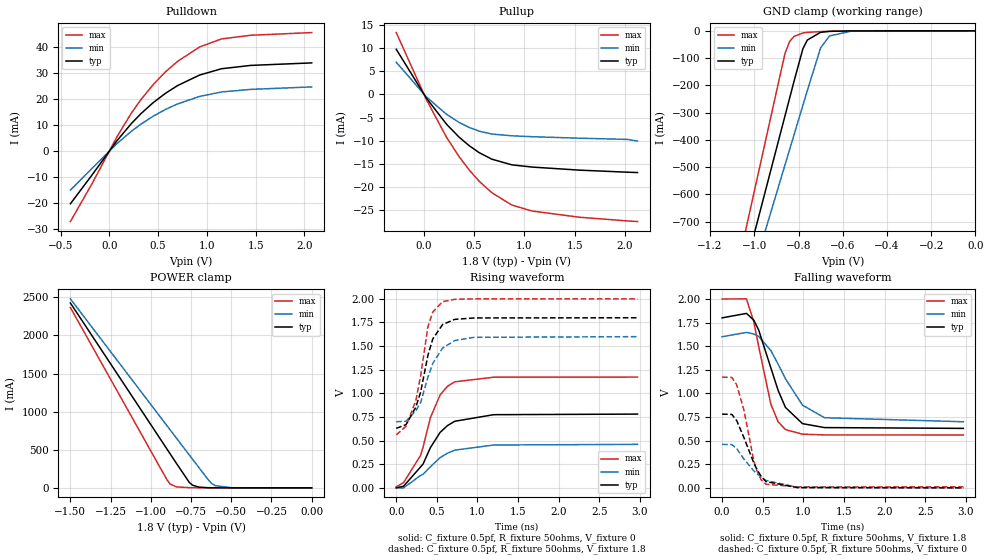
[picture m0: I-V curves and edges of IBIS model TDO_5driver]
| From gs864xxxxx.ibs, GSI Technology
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|  signals   TDO
[Model]   TDO_5driver
Model_type   3-state
Polarity   Non-Inverting
Vmeas =   0.9v
Cref  =   0pF
Rref  =   50
Vref  =   0.9v
|  variable   typ   min   max
C_comp   3.0pF   2.5pF   3.5pF
|  variable   typ   min   max
[Temperature Range]   50   0   100
|  variable   typ   min   max
[Voltage Range]   1.8   1.6   2.0
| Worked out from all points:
|   slope of the pulldown table from 0 to 0.27 V, typ, clamps not added: 22 ohm
|   slope of the pullup table from 0 to 0.27 V, typ, clamps not added: 35.9 ohm
|   GND clamp passes 1 mA (typ) near -0.63 V on its own axis
|   POWER clamp passes 1 mA (typ) near -0.62 V on its own axis
|   rising waveform, C_fixture 0.5pf, R_fixture 50ohms, V_fixture 0: 20-80 % time 364ps typ, 408ps min, 296ps max; typ from 0 V to 0.78 V
|   rising waveform, C_fixture 0.5pf, R_fixture 50ohms, V_fixture 1.8: 20-80 % time 201ps typ, 228ps min, 181ps max; typ from 0.63 V to 1.8 V
|   falling waveform, C_fixture 0.5pf, R_fixture 50ohms, V_fixture 1.8: 20-80 % time 278ps typ, 363ps min, 213ps max; typ from 1.8 V to 0.63 V
|   falling waveform, C_fixture 0.5pf, R_fixture 50ohms, V_fixture 0: 20-80 % time 227ps typ, 293ps min, 168ps max; typ from 0.78 V to 0 V
[Pulldown]
| voltage   I(typ)   I(min)   I(max)
-400mV    -20.27mA   -15.02mA   -27.07mA
-175mV    -9.067mA   -6.592mA   -12.36mA
75mV      3.788mA    2.71mA     5.252mA
225mV     10.47mA    7.513mA    14.46mA
325mV     14.33mA    10.29mA    19.74mA
450mV     18.52mA    13.32mA    25.45mA
575mV     22.07mA    15.88mA    30.29mA
700mV     25.05mA    18.02mA    34.34mA
925mV     29.07mA    20.88mA    39.82mA
1.15V     31.49mA    22.59mA    42.92mA
1.45V     32.77mA    23.58mA    44.32mA
2.075V    33.73mA    24.53mA    45.35mA
[Pullup]
| voltage (VDDQ-Vout) I(typ)   I(min)   I(max)
-275mV    9.762mA    6.959mA    13.37mA
25mV      -807.2uA   -552.3uA   -1.142mA
225mV     -6.446mA   -4.305mA   -9.267mA
350mV     -9.245mA   -6.06mA    -13.46mA
450mV     -11.09mA   -7.145mA   -16.33mA
550mV     -12.6mA    -7.951mA   -18.78mA
675mV     -14.01mA   -8.58mA    -21.26mA
875mV     -15.24mA   -8.959mA   -23.94mA
1.075V    -15.72mA   -9.151mA   -25.23mA
1.55V     -16.39mA   -9.479mA   -26.58mA
2.025V    -16.83mA   -9.737mA   -27.37mA
2.125V    -16.91mA   -10.1mA    -27.51mA
[GND Clamp]
| voltage   I(typ)   I(min)   I(max)
-1.5V     -2.3A      -2.224A    -2.415A
-880mV    -370.6mA   -543.1mA   -151.1mA
-860mV    -308.5mA   -489mA     -80.12mA
-840mV    -246.5mA   -434.9mA   -38.91mA
-820mV    -184.4mA   -380.9mA   -20.22mA
-780mV    -65.55mA   -272.8mA   -7.662mA
-760mV    -33.81mA   -218.9mA   -5.572mA
-700mV    -5.364mA   -62.59mA   -2.825mA
-660mV    -1.94mA    -18.77mA   -1.788mA
-560mV    -225.3uA   -949.8uA   -330.3uA
0V        -80.77pA   -306.2pA   -41.52pA
[POWER Clamp]
| voltage (VDDQ-Vout) I(typ)   I(min)   I(max)
-1.5V     2.426A     2.48A      2.366A
-900mV    510.3mA    816.5mA    107.6mA
-880mV    446.6mA    761.2mA    49.81mA
-840mV    319.2mA    650.6mA    11.91mA
-760mV    68.92mA    429.4mA    2.314mA
-740mV    34.64mA    374.2mA    1.835mA
-700mV    9.127mA    263.7mA    1.175mA
-640mV    1.574mA    98.15mA    523.4uA
-620mV    952.5uA    54.01mA    374.9uA
-600mV    595.9uA    29.29mA    258.4uA
-500mV    63.92uA    1.397mA    23.45uA
0V        110.2pA    1.372nA    38.5pA
[Ramp]
| voltage   typ   min   max
dV/dt_r   1.33/241p   1.13/295p   1.59/197p
dV/dt_f   1.32/240p   1.13/294p   1.57/196p
R_load  =   50ohms
[Rising Waveform]
C_fixture =   0.5pf
R_fixture =   50ohms
V_fixture =   0
| Time   V(typ)   V(min)   V(max)
0s        396.9uV    8.275uV    10.4mV
90ps      16.85mV    -68.67uV   55.1mV
300ps     221.9mV    131.5mV    344mV
330ps     251.9mV    143.8mV    429.9mV
420ps     424.9mV    222mV      742mV
540ps     586.9mV    319.7mV    983.8mV
630ps     658.5mV    366.3mV    1.074V
720ps     704.6mV    398.7mV    1.122V
1.2ns     774.3mV    453.4mV    1.171V
2.97ns    780.5mV    460.2mV    1.172V
[Rising Waveform]
C_fixture =   0.5pf
R_fixture =   50ohms
V_fixture =   1.8
V_fixture_min =   1.6
V_fixture_max =   2.0
| Time   V(typ)   V(min)   V(max)
0s        629.5mV    699.5mV    559.4mV
120ps     669mV      705.4mV    652.3mV
240ps     851.8mV    814.6mV    919.6mV
300ps     1.012V     903.2mV    1.183V
390ps     1.403V     1.172V     1.706V
450ps     1.576V     1.318V     1.861V
570ps     1.728V     1.479V     1.97V
720ps     1.783V     1.559V     1.995V
960ps     1.798V     1.593V     2V
2.97ns    1.8V       1.6V       2V
[Falling Waveform]
C_fixture =   0.5pf
R_fixture =   50ohms
V_fixture =   1.8
V_fixture_min =   1.6
V_fixture_max =   2.0
| Time   V(typ)   V(min)   V(max)
0s        1.8V       1.6V       2V
300ps     1.847V     1.646V     2.001V
390ps     1.776V     1.629V     1.76V
450ps     1.672V     1.604V     1.499V
600ps     1.271V     1.454V     885.6mV
690ps     1.031V     1.309V     699.1mV
780ps     851.4mV    1.155V     616.5mV
990ps     679.9mV    874.9mV    568.3mV
1.26ns    638.1mV    742.6mV    560.5mV
2.97ns    629.6mV    699.7mV    559.4mV
[Falling Waveform]
C_fixture =   0.5pf
R_fixture =   50ohms
V_fixture =   0
| Time   V(typ)   V(min)   V(max)
0s        780.5mV    460.2mV    1.172V
120ps     777.4mV    458mV      1.169V
180ps     711.9mV    415.4mV    1.091V
270ps     529mV      303.3mV    819.5mV
390ps     265.2mV    180.1mV    287.1mV
420ps     210mV      156.3mV    198.5mV
480ps     121.3mV    112.9mV    84.97mV
540ps     66.26mV    77.52mV    38.08mV
930ps     2.059mV    5.619mV    10.78mV
2.97ns    397.3uV    9.407uV    10.4mV
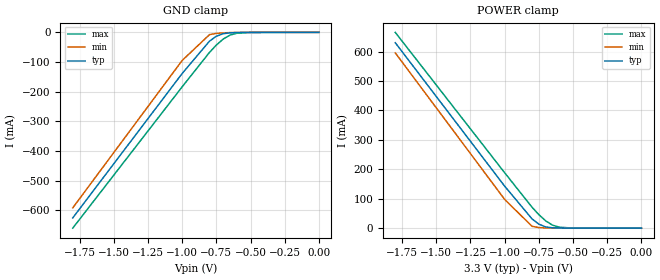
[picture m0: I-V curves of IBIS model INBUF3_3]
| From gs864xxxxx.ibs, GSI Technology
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| signals   A0-A18, CK, E1#, E@, E3#, BA#, BB#, BC#, BD#, W#,
|   ADV, G#, CKE#, ZZ
[Model]   INBUF3_3
Model_type   Input
Vinl  =   0.8v
Vinh  =   2.0v
|  variable   typ   min   max
C_comp   3.0pF   2.5pF   3.5pF
|  variable   typ   min   max
[Temperature Range]   50   0   100
|  variable   typ   min   max
[Voltage Range]   3.3   3.0   3.6
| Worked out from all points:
|   GND clamp passes 1 mA (typ) near -0.62 V on its own axis
|   POWER clamp passes 1 mA (typ) near -0.64 V on its own axis
[GND Clamp]
| voltage   typ   min   max
-1.8V     -625.4mA   -591.5mA   -659.9mA
-1V       -138.6mA   -94.6mA    -183.5mA
-800mV    -29.5mA    -7.6mA     -67.3mA
-750mV    -12.9mA    -3.4mA     -42.7mA
-700mV    -4.5mA     -1.7mA     -22.5mA
-650mV    -1.6mA     -800uA     -9.1mA
-600mV    -600uA     -300uA     -2.9mA
-500mV    -100uA     0A         -200uA
0V        0A         0A         0A
[POWER Clamp]
| voltage (VDDQ-Vout) typ   min   max
-1.8V     630mA      595.4mA    665.1mA
-1V       142.5mA    97.5mA     188.1mA
-800mV    31.4mA     6.2mA      71.1mA
-750mV    13.5mA     1.8mA      45.8mA
-700mV    4.1mA      800uA      24.7mA
-650mV    1.1mA      400uA      10.1mA
-600mV    400uA      200uA      3.1mA
-500mV    0A         0A         200uA
0V        0A         0A         0A
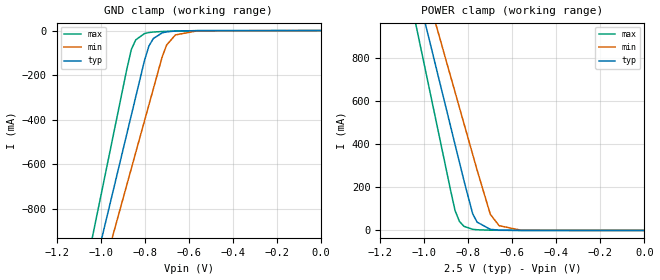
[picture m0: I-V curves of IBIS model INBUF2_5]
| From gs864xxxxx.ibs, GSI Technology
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| signals   A0-A18, CK, E1#, E@, E3#, BA#, BB#, BC#, BD#, W#,
|   ADV, G#, CKE#, ZZ
[Model]   INBUF2_5
Model_type   Input
Vinl  =   0.75v
Vinh  =   1.75v
|  variable   typ   min   max
C_comp   3.0pF   2.5pF   3.5pF
|  variable   typ   min   max
[Temperature Range]   50   0   100
|  variable   typ   min   max
[Voltage Range]   2.5   2.375   2.7
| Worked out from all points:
|   GND clamp passes 1 mA (typ) near -0.62 V on its own axis
|   POWER clamp passes 1 mA (typ) near -0.64 V on its own axis
[GND Clamp]
| voltage   typ   min   max
-1.5V     -3.013A    -2.915A    -3.16A
-880mV    -461.4mA   -690.4mA   -170.5mA
-860mV    -379.3mA   -618.8mA   -84.77mA
-840mV    -297.2mA   -547.2mA   -41.61mA
-800mV    -133mA     -404.1mA   -13.09mA
-780mV    -68.8mA    -332.6mA   -8.784mA
-760mV    -35.62mA   -261.1mA   -6.51mA
-720mV    -10.25mA   -118.2mA   -4.15mA
-700mV    -5.839mA   -65.31mA   -3.373mA
-660mV    -2.179mA   -19.59mA   -2.138mA
-560mV    -262.4uA   -1.004mA   -392.6uA
0V        -100.9pA   -273.4pA   -68.38pA
[POWER Clamp]
| voltage (VDDQ-Vout) typ   min   max
-1.5V     3.054A     2.953A     3.206A
-880mV    480.7mA    713.2mA    184.1mA
-860mV    397.8mA    641mA      91.6mA
-840mV    314.9mA    568.9mA    41.61mA
-820mV    232mA      496.7mA    19.43mA
-780mV    76.98mA    352.4mA    5.305mA
-760mV    38.66mA    280.3mA    3.294mA
-700mV    5.241mA    75.14mA    1.378mA
-660mV    1.62mA     22.22mA    896.3uA
-560mV    164.4uA    1.068mA    216.3uA
0V        178.4pA    685.8pA    76.45pA
